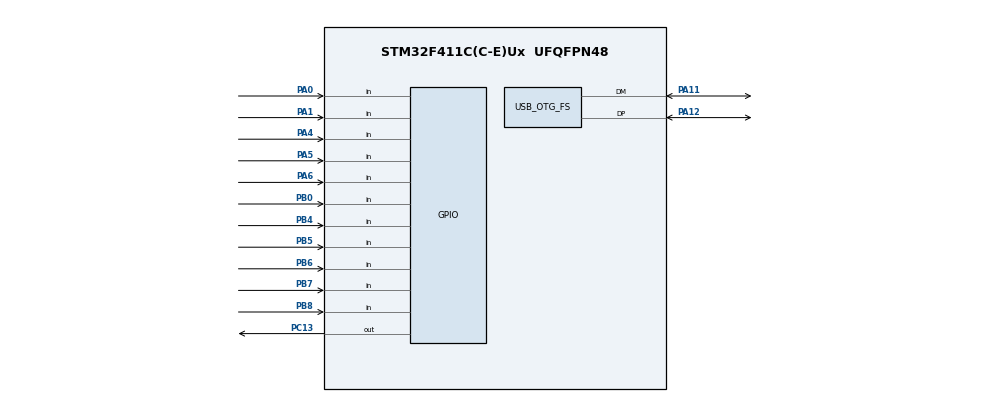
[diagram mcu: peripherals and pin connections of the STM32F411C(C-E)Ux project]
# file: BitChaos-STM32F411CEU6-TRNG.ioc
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Mcu.Family=STM32F4
Mcu.Name=STM32F411C(C-E)Ux
Mcu.Package=UFQFPN48
NVIC.OTG_FS_IRQn=true\:0\:0\:false\:false\:true\:false\:true\:true
NVIC.PriorityGroup=NVIC_PRIORITYGROUP_4
PA0-WKUP.Signal=GPIO_Input
PA1.Signal=GPIO_Input
PA11.Mode=Device_Only
PA11.Signal=USB_OTG_FS_DM
PA12.Mode=Device_Only
PA12.Signal=USB_OTG_FS_DP
PA13.Mode=Serial_Wire
PA13.Signal=SYS_JTMS-SWDIO
PA14.Mode=Serial_Wire
PA14.Signal=SYS_JTCK-SWCLK
PA4.Signal=GPIO_Input
PA5.Signal=GPIO_Input
PA6.Signal=GPIO_Input
PB0.Signal=GPIO_Input
PB4.Signal=GPIO_Input
PB5.Signal=GPIO_Input
PB6.Signal=GPIO_Input
PB7.Signal=GPIO_Input
PB8.Signal=GPIO_Input
PC13-ANTI_TAMP.Signal=GPIO_Output
PH0\ -\ OSC_IN.Mode=HSE-External-Oscillator
PH0\ -\ OSC_IN.Signal=RCC_OSC_IN
PH1\ -\ OSC_OUT.Mode=HSE-External-Oscillator
PH1\ -\ OSC_OUT.Signal=RCC_OSC_OUT
ProjectManager.HeapSize=0x200
ProjectManager.StackSize=0x400
ProjectManager.TargetToolchain=CMake
RCC.48MHZClocksFreq_Value=48000000
RCC.AHBFreq_Value=16000000
RCC.APB1Freq_Value=16000000
RCC.APB2Freq_Value=16000000
RCC.CortexFreq_Value=16000000
RCC.HSE_VALUE=25000000
RCC.HSI_VALUE=16000000
RCC.LSE_VALUE=32768
RCC.PLLM=15
RCC.PLLN=144
RCC.PLLQ=5
RCC.SYSCLKFreq_VALUE=16000000
RCC.VCOOutputFreq_Value=240000000
USB_DEVICE.CLASS_NAME_FS=CDC
USB_DEVICE.VirtualMode=Cdc
USB_DEVICE.VirtualModeFS=Cdc_FS
USB_OTG_FS.VirtualMode=Device_Only
VP_USB_DEVICE_VS_USB_DEVICE_CDC_FS.Mode=CDC_FS
board=custom

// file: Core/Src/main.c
/* USER CODE BEGIN Header */
/**
  ******************************************************************************
  * @file           : main.c
  * @brief          : Main program body
  ******************************************************************************
  * @attention
  *
  * Copyright (c) 2024 STMicroelectronics.
  * All rights reserved.
  *
  * This software is licensed under terms that can be found in the LICENSE file
  * in the root directory of this software component.
  * If no LICENSE file comes with this software, it is provided AS-IS.
  *
  ******************************************************************************
  */
/* USER CODE END Header */
#include "main.h"

/* USER CODE BEGIN Includes */
#include "usb_device.h"
#include "usbd_cdc_if.h"
#include "string.h"
#include "stdio.h"
#include "stddef.h"
#include "unistd.h"
/* USER CODE END Includes */

/* USER CODE BEGIN PV */
uint8_t usb_rx_buffer;  // Single-byte buffer for receiving data

uint16_t avg_number = 50;
char usb_tx_avg_buffer[30];

uint8_t msg[] = {0x1, 0x2, 0x3, 0x4};
uint8_t encrypted[4] = {0};
uint8_t decrypted[4] = {0};
/* USER CODE END PV */

void SystemClock_Config(void);
static void MX_GPIO_Init(void);
/* USER CODE BEGIN PFP */
uint16_t read_ring_oscillator(void);
uint16_t get_avg(uint16_t num);
uint32_t key_gen32(uint16_t trng);
void encrypt(uint8_t msg[], uint8_t buffer[], uint16_t len, uint32_t key);
void decrypt(uint8_t cipher[], uint8_t buffer[], uint16_t len, uint32_t key);
/* USER CODE END PFP */

int main(void)
{

  /* MCU Configuration--------------------------------------------------------*/

  /* Reset of all peripherals, Initializes the Flash interface and the Systick. */
  HAL_Init();

  /* Configure the system clock */
  SystemClock_Config();

  /* Initialize all configured peripherals */
  MX_GPIO_Init();
  MX_USB_DEVICE_Init();
  /* USER CODE BEGIN 2 */

  HAL_Delay(10000);

  uint16_t avg = get_avg(avg_number);

  printf("Average: %d\r\n", avg);

  // sprintf(usb_tx_avg_buffer, "Average: %d\r\n", avg);
  // CDC_Transmit_FS((uint16_t *)usb_tx_avg_buffer, strlen(usb_tx_avg_buffer));

  /* USER CODE END 2 */

  /* Infinite loop */
  while (1)
  {
    CDC_Transmit_FS(NULL,0);
    HAL_Delay(100);

    if (usb_rx_buffer == 'G') {

      usb_rx_buffer = 0;

      HAL_Delay(2000);

      uint16_t random_number = read_ring_oscillator();

      printf("Random number: %u\r\n", random_number);

      HAL_Delay(2000);

      uint32_t key = key_gen32(random_number);

      printf("Key: 0x%X\r\n", key);

      HAL_Delay(2000);

      encrypt(msg, encrypted, 4, key);
      decrypt(encrypted, decrypted, 4, key);

      printf("Size Of Encryption: %u\r\n", sizeof(encrypted));
      for (int i = 0; i < 4; i++) {
        printf("%02x ", encrypted[i]);
      }

      printf("\r\n");

      HAL_Delay(2000);

      printf("Size of Decryption: %u\r\n", sizeof(decrypted));
      for (int i = 0; i < 4; i++) {
        printf("%02x ", decrypted[i]);
      }

      printf("\r\n");
    }
  }
}

void SystemClock_Config(void)
{
  RCC_OscInitTypeDef RCC_OscInitStruct = {0};
  RCC_ClkInitTypeDef RCC_ClkInitStruct = {0};

  /** Configure the main internal regulator output voltage
  */
  __HAL_RCC_PWR_CLK_ENABLE();
  __HAL_PWR_VOLTAGESCALING_CONFIG(PWR_REGULATOR_VOLTAGE_SCALE1);

  /** Initializes the RCC Oscillators according to the specified parameters
  * in the RCC_OscInitTypeDef structure.
  */
  RCC_OscInitStruct.OscillatorType = RCC_OSCILLATORTYPE_HSE;
  RCC_OscInitStruct.HSEState = RCC_HSE_ON;
  RCC_OscInitStruct.PLL.PLLState = RCC_PLL_ON;
  RCC_OscInitStruct.PLL.PLLSource = RCC_PLLSOURCE_HSE;
  RCC_OscInitStruct.PLL.PLLM = 15;
  RCC_OscInitStruct.PLL.PLLN = 144;
  RCC_OscInitStruct.PLL.PLLP = RCC_PLLP_DIV4;
  RCC_OscInitStruct.PLL.PLLQ = 5;
  if (HAL_RCC_OscConfig(&RCC_OscInitStruct) != HAL_OK)
  {
    Error_Handler();
  }

  /** Initializes the CPU, AHB and APB buses clocks
  */
  RCC_ClkInitStruct.ClockType = RCC_CLOCKTYPE_HCLK|RCC_CLOCKTYPE_SYSCLK
                              |RCC_CLOCKTYPE_PCLK1|RCC_CLOCKTYPE_PCLK2;
  RCC_ClkInitStruct.SYSCLKSource = RCC_SYSCLKSOURCE_PLLCLK;
  RCC_ClkInitStruct.AHBCLKDivider = RCC_SYSCLK_DIV1;
  RCC_ClkInitStruct.APB1CLKDivider = RCC_HCLK_DIV2;
  RCC_ClkInitStruct.APB2CLKDivider = RCC_HCLK_DIV1;

  if (HAL_RCC_ClockConfig(&RCC_ClkInitStruct, FLASH_LATENCY_1) != HAL_OK)
  {
    Error_Handler();
  }
}

static void MX_GPIO_Init(void)
{
  GPIO_InitTypeDef GPIO_InitStruct = {0};

  /* GPIO Ports Clock Enable */
  __HAL_RCC_GPIOC_CLK_ENABLE();
  __HAL_RCC_GPIOH_CLK_ENABLE();
  __HAL_RCC_GPIOA_CLK_ENABLE();
  __HAL_RCC_GPIOB_CLK_ENABLE();

  /*Configure GPIO pin Output Level */
  HAL_GPIO_WritePin(GPIOC, GPIO_PIN_13, GPIO_PIN_RESET);

  /*Configure GPIO pin : PC13 */
  GPIO_InitStruct.Pin = GPIO_PIN_13;
  GPIO_InitStruct.Mode = GPIO_MODE_OUTPUT_PP;
  GPIO_InitStruct.Pull = GPIO_NOPULL;
  GPIO_InitStruct.Speed = GPIO_SPEED_FREQ_LOW;
  HAL_GPIO_Init(GPIOC, &GPIO_InitStruct);

  /*Configure GPIO pins : PA0 PA1 PA4 PA5
                           PA6 */
  GPIO_InitStruct.Pin = GPIO_PIN_0|GPIO_PIN_1|GPIO_PIN_4|GPIO_PIN_5
                          |GPIO_PIN_6;
  GPIO_InitStruct.Mode = GPIO_MODE_INPUT;
  GPIO_InitStruct.Pull = GPIO_NOPULL;
  HAL_GPIO_Init(GPIOA, &GPIO_InitStruct);

  /*Configure GPIO pins : PB0 PB4 PB5 PB6
                           PB7 PB8 */
  GPIO_InitStruct.Pin = GPIO_PIN_0|GPIO_PIN_4|GPIO_PIN_5|GPIO_PIN_6
                          |GPIO_PIN_7|GPIO_PIN_8;
  GPIO_InitStruct.Mode = GPIO_MODE_INPUT;
  GPIO_InitStruct.Pull = GPIO_NOPULL;
  HAL_GPIO_Init(GPIOB, &GPIO_InitStruct);

}

/* USER CODE BEGIN 4 */

int _write(int file, char *data, int len) {

  if (file == STDOUT_FILENO || file == STDERR_FILENO) {
    CDC_Transmit_FS((uint16_t *)data, len);
  }

  return len;
}

void USB_CDC_RxHandler(uint8_t* Buf, uint32_t Len)
{
    usb_rx_buffer = Buf[0];
}

uint16_t read_ring_oscillator(void)
{
  uint16_t random_value = 0;

  random_value |= HAL_GPIO_ReadPin(GPIOA, GPIO_PIN_0) << 0;
  random_value |= HAL_GPIO_ReadPin(GPIOA, GPIO_PIN_1) << 1;
  random_value |= HAL_GPIO_ReadPin(GPIOA, GPIO_PIN_4) << 2;
  random_value |= HAL_GPIO_ReadPin(GPIOA, GPIO_PIN_5) << 3;
  random_value |= HAL_GPIO_ReadPin(GPIOA, GPIO_PIN_6) << 4;
  random_value |= HAL_GPIO_ReadPin(GPIOB, GPIO_PIN_8) << 5;
  random_value |= HAL_GPIO_ReadPin(GPIOB, GPIO_PIN_7) << 6;
  random_value |= HAL_GPIO_ReadPin(GPIOB, GPIO_PIN_6) << 7;
  random_value |= HAL_GPIO_ReadPin(GPIOB, GPIO_PIN_5) << 8;
  random_value |= HAL_GPIO_ReadPin(GPIOB, GPIO_PIN_4) << 9;
  return random_value;
}

uint16_t get_avg(uint16_t num) {

    uint16_t sum = 0;
    uint16_t n = 0;
    char usb_tx2_avg_buffer[30];

    for (int i = 0; i < num; i++) {

      uint16_t random_value = read_ring_oscillator();
      printf("TRNG Number: %d\r\n", random_value);
      sum += random_value;
      n++;
      HAL_GPIO_TogglePin(GPIOC, GPIO_PIN_13);
      HAL_Delay(2000);

    }

    return (float) sum / n;
}

uint32_t key_gen32(uint16_t trng) {
    uint32_t key = 0;
    for (int i = 0; i < 4; i++) {
        key |= (trng << (i * 8));
    }
    return key;
}

void encrypt(uint8_t msg[], uint8_t buffer[], uint16_t len, uint32_t key) {
    int j = 0;
    for (uint16_t i = 0; i < len; i++) {
        buffer[i] = msg[i] ^ (key >> (j * 8));
        j++;
        if (j == 4) {
            j = 0;
        }
    }
}

void decrypt(uint8_t cipher[], uint8_t buffer[], uint16_t len, uint32_t key) {
    int j = 0;
    for (uint16_t i = 0; i < len; i++) {
        buffer[i] = cipher[i] ^ (key >> (j * 8));
        j++;
        if (j == 4) {
            j = 0;
        }
    }
}

/* USER CODE END 4 */

void Error_Handler(void)
{
  __disable_irq();
  while (1)
  {
  }
}
